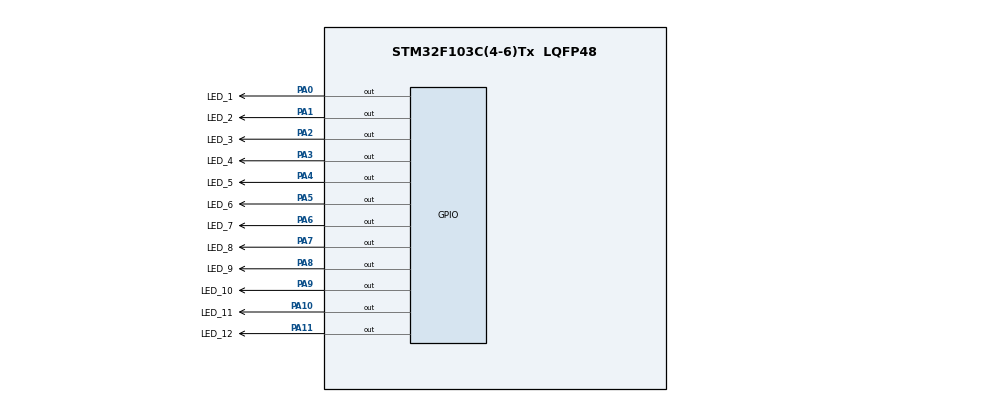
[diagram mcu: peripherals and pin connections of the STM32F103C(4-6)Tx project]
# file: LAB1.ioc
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Mcu.Family=STM32F1
Mcu.Name=STM32F103C(4-6)Tx
Mcu.Package=LQFP48
NVIC.PriorityGroup=NVIC_PRIORITYGROUP_4
PA0-WKUP.GPIO_Label=LED_1
PA0-WKUP.Signal=GPIO_Output
PA1.GPIO_Label=LED_2
PA1.Signal=GPIO_Output
PA10.GPIO_Label=LED_11
PA10.Signal=GPIO_Output
PA11.GPIO_Label=LED_12
PA11.Signal=GPIO_Output
PA2.GPIO_Label=LED_3
PA2.Signal=GPIO_Output
PA3.GPIO_Label=LED_4
PA3.Signal=GPIO_Output
PA4.GPIO_Label=LED_5
PA4.Signal=GPIO_Output
PA5.GPIO_Label=LED_6
PA5.Signal=GPIO_Output
PA6.GPIO_Label=LED_7
PA6.Signal=GPIO_Output
PA7.GPIO_Label=LED_8
PA7.Signal=GPIO_Output
PA8.GPIO_Label=LED_9
PA8.Signal=GPIO_Output
PA9.GPIO_Label=LED_10
PA9.Signal=GPIO_Output
ProjectManager.HeapSize=0x200
ProjectManager.StackSize=0x400
ProjectManager.TargetToolchain=STM32CubeIDE
RCC.APB1Freq_Value=8000000
RCC.APB2Freq_Value=8000000
board=custom

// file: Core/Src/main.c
/* USER CODE BEGIN Header */
/**
  ******************************************************************************
  * @file           : main.c
  * @brief          : Main program body
  ******************************************************************************
  * @attention
  *
  * Copyright (c) 2024 STMicroelectronics.
  * All rights reserved.
  *
  * This software is licensed under terms that can be found in the LICENSE file
  * in the root directory of this software component.
  * If no LICENSE file comes with this software, it is provided AS-IS.
  *
  ******************************************************************************
  */
/* USER CODE END Header */
#include "main.h"

void SystemClock_Config(void);
static void MX_GPIO_Init(void);

int main(void)
{

  /* MCU Configuration--------------------------------------------------------*/

  /* Reset of all peripherals, Initializes the Flash interface and the Systick. */
  HAL_Init();

  /* Configure the system clock */
  SystemClock_Config();

  /* Initialize all configured peripherals */
  MX_GPIO_Init();
  /* USER CODE BEGIN 2 */
  int NUM [10][7]=
	{
		{0,0,0,0,0,0,1},
		{1,0,0,1,1,1,1},
		{0,0,1,0,0,1,0},
		{0,0,0,0,1,1,0},
		{1,0,0,1,1,0,0},
		{0,1,0,0,1,0,0},
		{0,1,0,0,0,0,0},
		{0,0,0,1,1,1,1},
		{0,0,0,0,0,0,0},
		{0,0,0,0,1,0,0}
	};
	void display7SEG(int num)
	{
		HAL_GPIO_WritePin ( A_GPIO_Port , A_Pin  ,NUM[num] [0] );
		HAL_GPIO_WritePin ( B_GPIO_Port , B_Pin  ,NUM[num] [1] );
		HAL_GPIO_WritePin ( C_GPIO_Port , C_Pin  ,NUM[num] [2] );
		HAL_GPIO_WritePin ( D_GPIO_Port , D_Pin  ,NUM[num] [3] );
		HAL_GPIO_WritePin ( E_GPIO_Port , E_Pin  ,NUM[num] [4] );
		HAL_GPIO_WritePin ( F_GPIO_Port , F_Pin  ,NUM[num] [5] );
		HAL_GPIO_WritePin ( G_GPIO_Port , G_Pin  ,NUM[num] [6] );
	};
	void display7SEG1(int num)
		{
			HAL_GPIO_WritePin ( a_GPIO_Port , a_Pin  ,NUM[num] [0] );
			HAL_GPIO_WritePin ( b_GPIO_Port , b_Pin  ,NUM[num] [1] );
			HAL_GPIO_WritePin ( c_GPIO_Port , c_Pin  ,NUM[num] [2] );
			HAL_GPIO_WritePin ( d_GPIO_Port , d_Pin  ,NUM[num] [3] );
			HAL_GPIO_WritePin ( e_GPIO_Port , e_Pin  ,NUM[num] [4] );
			HAL_GPIO_WritePin ( f_GPIO_Port , f_Pin  ,NUM[num] [5] );
			HAL_GPIO_WritePin ( g_GPIO_Port , g_Pin  ,NUM[num] [6] );
		};
	  /* USER CODE END 2 */
	#define RED 			0
	#define YELLOW			1
	#define GREEN 			2
		int status1 = RED, count1 = 5;
		int status2 = GREEN, count2 = 3;
	  /* Infinite loop */
	  while (1)
	  {
		  display7SEG1(count2);
		  display7SEG(count1);
		  count1--;
		  count2--;
		  switch (status1)
		  {
		  case GREEN:
			  HAL_GPIO_WritePin(LED_RED1_GPIO_Port, LED_RED1_Pin, RESET);
			  HAL_GPIO_WritePin(LED_YELLOW1_GPIO_Port, LED_YELLOW1_Pin, RESET);
			  HAL_GPIO_WritePin(LED_GREEN1_GPIO_Port, LED_GREEN1_Pin, SET);
			  if (count1 <= 0)
			  {
				  status1 = YELLOW;
				  count1 = 2;
			  }
			  break;

		  case YELLOW:
			  HAL_GPIO_WritePin(LED_RED1_GPIO_Port, LED_RED1_Pin, RESET);
			  HAL_GPIO_WritePin(LED_YELLOW1_GPIO_Port, LED_YELLOW1_Pin, SET);
			  HAL_GPIO_WritePin(LED_GREEN1_GPIO_Port, LED_GREEN1_Pin, RESET);
			  if (count1 <= 0)
			  {
				  status1 = RED;
				  count1 = 5;
			  }
			  break;
		  case RED:
			  HAL_GPIO_WritePin(LED_RED1_GPIO_Port, LED_RED1_Pin, SET);
			  HAL_GPIO_WritePin(LED_YELLOW1_GPIO_Port, LED_YELLOW1_Pin, RESET);
			  HAL_GPIO_WritePin(LED_GREEN1_GPIO_Port, LED_GREEN1_Pin, RESET);
			  if (count1 <= 0)
			  {
				  status1 = GREEN;
				  count1 = 3;
			  }
			  break;
		  }

		  switch (status2)
		  {
		  case GREEN:
			  HAL_GPIO_WritePin(LED_RED2_GPIO_Port, LED_RED2_Pin, RESET);
			  HAL_GPIO_WritePin(LED_YELLOW2_GPIO_Port, LED_YELLOW2_Pin, RESET);
			  HAL_GPIO_WritePin(LED_GREEN2_GPIO_Port, LED_GREEN2_Pin, SET);
			  if (count2 <= 0)
			  {
				  status2 = YELLOW;
				  count2 = 2;
			  }
			  break;

		  case YELLOW:
			  HAL_GPIO_WritePin(LED_RED2_GPIO_Port, LED_RED2_Pin, RESET);
			  HAL_GPIO_WritePin(LED_YELLOW2_GPIO_Port, LED_YELLOW2_Pin, SET);
			  HAL_GPIO_WritePin(LED_GREEN2_GPIO_Port, LED_GREEN2_Pin, RESET);
			  if (count2 <= 0)
			  {
				  status2 = RED;
				  count2 = 5;
			  }
			  break;
		  case RED:
			  HAL_GPIO_WritePin(LED_RED2_GPIO_Port, LED_RED2_Pin, SET);
			  HAL_GPIO_WritePin(LED_YELLOW2_GPIO_Port, LED_YELLOW2_Pin, RESET);
			  HAL_GPIO_WritePin(LED_GREEN2_GPIO_Port, LED_GREEN2_Pin, RESET);
			  if (count2 <= 0)
			  {
				  status2 = GREEN;
				  count2 = 3;
			  }
			  break;
		  }
		  HAL_Delay(1000);
	    /* USER CODE BEGIN 3 */
	  }
}

void SystemClock_Config(void)
{
  RCC_OscInitTypeDef RCC_OscInitStruct = {0};
  RCC_ClkInitTypeDef RCC_ClkInitStruct = {0};

  /** Initializes the RCC Oscillators according to the specified parameters
  * in the RCC_OscInitTypeDef structure.
  */
  RCC_OscInitStruct.OscillatorType = RCC_OSCILLATORTYPE_HSI;
  RCC_OscInitStruct.HSIState = RCC_HSI_ON;
  RCC_OscInitStruct.HSICalibrationValue = RCC_HSICALIBRATION_DEFAULT;
  RCC_OscInitStruct.PLL.PLLState = RCC_PLL_NONE;
  if (HAL_RCC_OscConfig(&RCC_OscInitStruct) != HAL_OK)
  {
    Error_Handler();
  }

  /** Initializes the CPU, AHB and APB buses clocks
  */
  RCC_ClkInitStruct.ClockType = RCC_CLOCKTYPE_HCLK|RCC_CLOCKTYPE_SYSCLK
                              |RCC_CLOCKTYPE_PCLK1|RCC_CLOCKTYPE_PCLK2;
  RCC_ClkInitStruct.SYSCLKSource = RCC_SYSCLKSOURCE_HSI;
  RCC_ClkInitStruct.AHBCLKDivider = RCC_SYSCLK_DIV1;
  RCC_ClkInitStruct.APB1CLKDivider = RCC_HCLK_DIV1;
  RCC_ClkInitStruct.APB2CLKDivider = RCC_HCLK_DIV1;

  if (HAL_RCC_ClockConfig(&RCC_ClkInitStruct, FLASH_LATENCY_0) != HAL_OK)
  {
    Error_Handler();
  }
}

static void MX_GPIO_Init(void)
{
  GPIO_InitTypeDef GPIO_InitStruct = {0};

  /* GPIO Ports Clock Enable */
  __HAL_RCC_GPIOA_CLK_ENABLE();
  __HAL_RCC_GPIOB_CLK_ENABLE();

  /*Configure GPIO pin Output Level */
  HAL_GPIO_WritePin(GPIOA, LED_RED1_Pin|LED_YELLOW1_Pin|LED_GREEN1_Pin|LED_RED2_Pin
                          |LED_YELLOW2_Pin|LED_GREEN2_Pin|a_Pin|b_Pin
                          |c_Pin|d_Pin|e_Pin|f_Pin
                          |g_Pin, GPIO_PIN_RESET);

  /*Configure GPIO pin Output Level */
  HAL_GPIO_WritePin(GPIOB, A_Pin|B_Pin|C_Pin|D_Pin
                          |E_Pin|F_Pin|G_Pin, GPIO_PIN_RESET);

  /*Configure GPIO pins : LED_RED1_Pin LED_YELLOW1_Pin LED_GREEN1_Pin LED_RED2_Pin
                           LED_YELLOW2_Pin LED_GREEN2_Pin a_Pin b_Pin
                           c_Pin d_Pin e_Pin f_Pin
                           g_Pin */
  GPIO_InitStruct.Pin = LED_RED1_Pin|LED_YELLOW1_Pin|LED_GREEN1_Pin|LED_RED2_Pin
                          |LED_YELLOW2_Pin|LED_GREEN2_Pin|a_Pin|b_Pin
                          |c_Pin|d_Pin|e_Pin|f_Pin
                          |g_Pin;
  GPIO_InitStruct.Mode = GPIO_MODE_OUTPUT_PP;
  GPIO_InitStruct.Pull = GPIO_NOPULL;
  GPIO_InitStruct.Speed = GPIO_SPEED_FREQ_LOW;
  HAL_GPIO_Init(GPIOA, &GPIO_InitStruct);

  /*Configure GPIO pins : A_Pin B_Pin C_Pin D_Pin
                           E_Pin F_Pin G_Pin */
  GPIO_InitStruct.Pin = A_Pin|B_Pin|C_Pin|D_Pin
                          |E_Pin|F_Pin|G_Pin;
  GPIO_InitStruct.Mode = GPIO_MODE_OUTPUT_PP;
  GPIO_InitStruct.Pull = GPIO_NOPULL;
  GPIO_InitStruct.Speed = GPIO_SPEED_FREQ_LOW;
  HAL_GPIO_Init(GPIOB, &GPIO_InitStruct);

}

void Error_Handler(void)
{
  __disable_irq();
  while (1)
  {
  }
}
